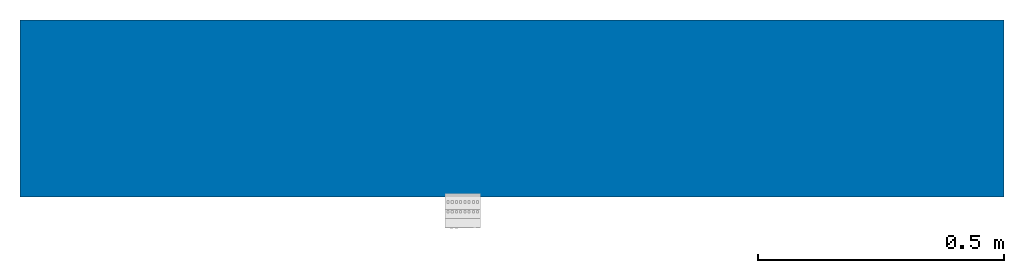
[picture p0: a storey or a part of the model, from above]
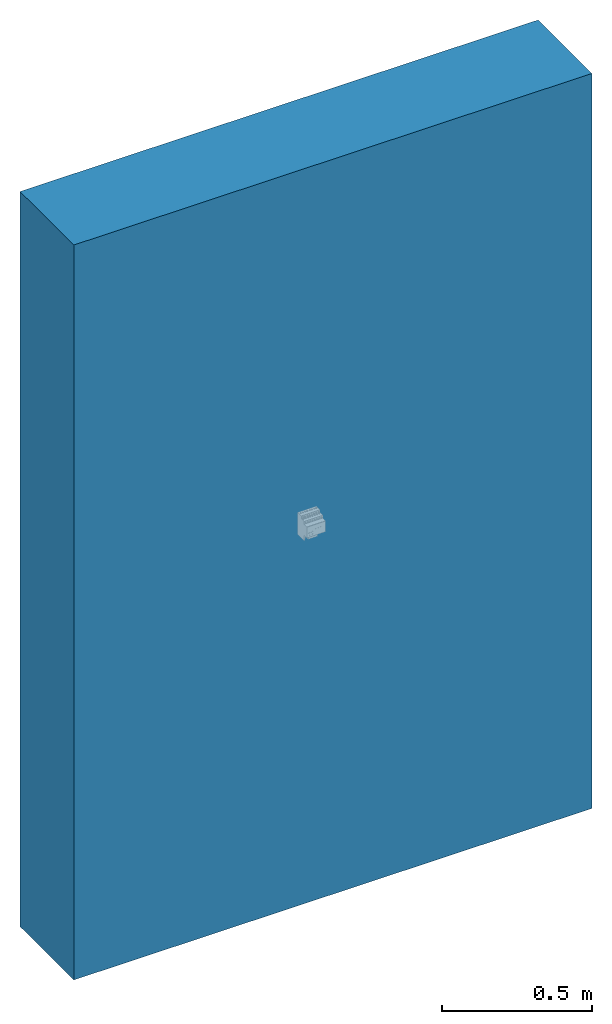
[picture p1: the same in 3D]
Properties of the parts of a building model (IFC2X3)

# File
Description: ViewDefinition [CoordinationView_V2.0]
File name: Projektnummer
Time: 2019-08-29T12:07:32
Written by: The EXPRESS Data Manager Version 5.02.0100.07 : 28 Aug 2013
Made in: 20160225_1515(x64) - Exporter 17.0.416.0 - Alternate UI 17.12.14.0
Comment: STEP Physical File produced by: The EXPRESS Data Manager Version 5.02.0100.07 : 28 Aug 2013 * Module: EDMstepFileFactory/EDMstandAlone * Creation date: Thu Aug 29 12:07:32 2019 * Host: B-BIM-NB-4736 * Database: C:\Users\Enkler\AppData\Local\Temp\{A3307029-4F48-4318-888E-B1E9CAFF832D}\ifc * Database version: 5507 * Database creation date: Thu Aug 29 12:07:31 2019 * Schema: IFC2X3 * Model: DataRepository.ifc * Model creation date: Thu Aug 29 12:07:31 2019 * Header model: DataRepository.ifc_HeaderModel * Header model creation date: Thu Aug 29 12:07:31 2019 * EDMuser: sdai-user * EDMgroup: sdai-group * License ID and type: 5605 : Permanent license. Expiry date: * EDMstepFileFactory options: 020000

# IfcProject, Projektnummer
LongName: Projektname; Phase: Projektstatus

# IfcSite, Default
RefLatitude: 52, 30, 59, 765625; RefLongitude: 13, 23, 59, 998626; RefElevation: 0 m
Sonstige - Kategorie: Projektinformationen; Kundenname: Bauherr; Projektadresse: Projektadresse; Projektausgabedatum: Projekt Datum; Projektname: Projektname; Projektnummer: Projektnummer; Projektstatus: Projektstatus; Verfasser eMail: E-Mail; Verfasser Firma 1: Firma 1; Verfasser Firma 2: Firma 2; Verfasser PLZ Ort: PLZ Ort; Verfasser Strasse: Strasse; Verfasser Telefax: Telefax; Verfasser Telefon: Telefon

# IfcBuilding
Pset_BuildingCommon - NumberOfStoreys: 1
Sonstige - Kategorie: Projektinformationen; Kundenname: Bauherr; Projektadresse: Projektadresse; Projektausgabedatum: Projekt Datum; Projektname: Projektname; Projektnummer: Projektnummer; Projektstatus: Projektstatus; Verfasser eMail: E-Mail; Verfasser Firma 1: Firma 1; Verfasser Firma 2: Firma 2; Verfasser PLZ Ort: PLZ Ort; Verfasser Strasse: Strasse; Verfasser Telefax: Telefax; Verfasser Telefon: Telefon

# IfcBuildingStorey, Ebene 0
LongName: Ebene 0; Elevation: 0 m
Sonstige - Kategorie: Ebenen; Familienname: Ebene; Familie: Ebene: Ebene; Familie und Typ: Ebene: Ebene; Typ: Ebene: Ebene; Typ-ID: Ebene: Ebene
ID-Daten - Typname: Ebene; Tragwerk: no; Gebäudegeschoss: yes; Name: Ebene 0
Grafiken - Farbe: 16711680; Linienmuster: Verdeckt; Linienstärke: 1; Symbol: Beschriftung Ebene: Beschriftung Ebene; Symbol bei Ende 1 Standard: no; Symbol bei Ende 2 Standard: yes
Abhängigkeiten - Basishöhe: Projekt-Basispunkt; Ansicht: 0 m
Abmessungen - Höhe für Berechnung: 0 m

# IfcBuildingElementProxy: GIRA_210800_ENG, GIRA_210800_ENG:GIRA_210800_ENG:389702
In: Ebene 0
Type - Material: White
Type - Abhängigkeiten - Vorgabe-Ansicht: 1.2192 m
Type - Allgemein - Bus connection included: no; Bus connection included YesNo: no; Bus module detachable: no; Bus system KNX: yes; Bus system KNX radio: no; Bus system KNX radio YesNo: no; Bus system KNX YesNo: yes; Bus system LON: no; Bus system LON YesNo: no; Bus system Powernet: no; Bus system Powernet YesNo: no; Bus system radio frequent: no; Bus system radio frequent YesNo: no; Degree of protection (IP) Text: IP20; HeinzeBIM: https://www.heinze.de/bim/dali-gateway-tunable-wh-plus-knx-dra/f92e1bc0089f869e15c3525b0f4f43e7c166bf0a; Local operation/hand operation YesNo: no; Model: Control module; Mounting method: DRA (DIN-rail adapter); Mounting method Text: DRA (DIN-rail adapter); Other bus systems: Other; Other bus systems Text: Other; Radio frequent bidirectional: no; With LED indication YesNo: yes
Type - Daten - Number of outputs: 6; Width in number of modular spacings Number: 4
Type - ID-Daten - Beschreibung: DALI gateway Tun.WH Plus DRA KNX,KNX DALI gateway Tunable White Plus,,,Features:,- Control of lights and other applications with DALI operating units in KNX installations.,- Adjustment of colour temperature for lights with DALI Device Type 8 (Colour Type: Colour Temperature) for Tunable White according to IEC 62386-209.,- Short-circuit protection, overvoltage protection, overload protection.,- Switching and dimming of a maximum of 64 lights with DALI operating devices.,- Up to 6 different Up to addressing types enable control of individual or grouped DALI lights via KNX telegrams.,- Up to 32 independent DALI groups are available for group addressing. These can be expanded by 64 individually addressable DALI device channels.,- Control of DALI operating devices of device type Colour Control" (DALI Device Type 8, Colour Type: Colour Temperature) in specific configuration "Tunable White (TW)". Control of colour temperature vial relative or absolute dimming and also via scenes and effects.,- Central control of all connected DALI components possible (broadcast).,- Manual operation independent of the bus (building site operation with broadcast control). Control of switching condition and brightness.,- Feedback of DALI error status or DALI short circuit and signalling of power supply failure.,- Central switching function.,- Group feedback of all switching conditions possible.,- 16 light scenes.,- Effect control for realising dynamic lighting moods. 16 effects with up to 16 effect steps each. Timer enabling starting and stopping of effects independent of time and day of the week.,Group and device functions:,- Switching and brightness value: Active or passive feedback functions.,- Setting brightness limits (minimum brightness or maximum brightness).,- Dimming behaviour and dimming characteristics can be parameterised.,- Bulb-saving switch-on and switch-off,- Block function or forced setting function can be parameterised.,- Time functions (switch-on switch-off delay, staircase light function - also with advance warning function).,- Elapsed operating time meter.,- DALI power-ON level and DALI system-failure level can be set.,- Reactions in case of bus voltage failure and restoration can be set following ETS programming process.,- Control of colour temperature via absolute dimming and relative dimming, dimming behaviour can be parameterised, adjustable minimum and maximum colour temperature, feedback for current and invalid colour temperature.,Operation of emergency lighting:,- Integration of the device into DALI emergency lighting systems. The DALI gateway is able to integrate DALI standard operating devices for lighting control in accordance with IEC 62386-101 (DALI system) and IEC 62386-102 (control gear) as an emergency light in centrally-powered emergency lighting systems.,- Monitoring for failure of the general power supply.,- Behaviour can be set for the end of emergency mode.,- Brightness and colour temperature adjustable during activate emergency mode.,ETS plug-in:,- DALI initial start-up without additional software comnponents. Identification, addressing and assigning of DALI operating devices takes place in the ETS plug-in.,- Assignment of individual devices to groups is also without programming connection to the device.,- Compatibility check of DALI device type for assigning DALI operating devices.,- Compatibility mode for support of operating devices which are not DALI-compliant.,- Partial DALI start-up.,- Test function of all created DALI groups or DALI operating devices.,- Exporting or importing a template.,- Printing function to create a report.,,Notes :,- Operation of emergency lighting systems:, Statutory and normative specifications vary by country. In any case, the user professional planner should ensure that the specific guidelines are observed.,- VDE approval in accordance with EN 60669-1, EN 60669-2-1.,- Configuration and start-up of the device from ETS 4.2 or ETS 5 (recommendation)."; GTIN: 4010337032878; HAN: 210800; Hersteller: Gira; Typname: DALI gateway Tunable WH Plus KNX DRA; URL: https://www.gira.de/
Type - Sonstige - Kategorie: Elektroinstallationen; Familienname: GIRA_210800_ENG
Pset_BuildingElementProxyCommon - Reference: GIRA_210800_ENG
Pset_ManufacturerTypeInformation - Manufacturer: Gira
Abhängigkeiten - Basisbauteil: Basiswand : MW 24.0 WD 12.0; Ebene: Ebene: Ebene 0; Erhebung: 1.56189 m
Abmessungen - Fläche: 0.0179427 m2; Volumen: 0.000458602 m3
ID-Daten - Kennzeichen: 1
Phasen - Phase erstellt: Phase 1
Sonstige - Bauteillistenebene: Ebene: Ebene 0; Familie: GIRA_210800_ENG: GIRA_210800_ENG; Familie und Typ: GIRA_210800_ENG: GIRA_210800_ENG; Typ: GIRA_210800_ENG: GIRA_210800_ENG; Typ-ID: GIRA_210800_ENG: GIRA_210800_ENG

# IfcWallStandardCase: Basiswand:MW 24.0 WD 12.0, Basiswand:MW 24.0 WD 12.0:388643
In: Ebene 0
Type - PredefinedType: STANDARD; Material: Wärmedämmung - hart 0.12 m, Mauerwerk - Ziegel, verputzt 0.24 m
Type - Analytische Eigenschaften - Absorptionsgrad: 0.7; Rauigkeit: 3; Thermischer Widerstand (R): 3.87302; Thermisch wirksame Masse: 316537; Wärmeübergangskoeffizient (U): 0.258197
Type - Grafiken - Farbfüllung für groben Maßstab: 0; Füllmuster für groben Maßstab: Standard - Füllung
Type - ID-Daten - Beschreibung: Mauerwerk 24.0 cm, Wärmedämmung 12.0 cm; Typenkommentare: Mehrschaliges Mauerwerk; Typname: MW 24.0 WD 12.0
Type - Konstruktion - Abschluss an Öffnungen: Keine; Abschluss an Wänden: Keine; Breite: 0.36 m; Funktion: Außen
Type - Materialien und Oberflächen - Tragendes Material: Mauerwerk - Ziegel, verputzt
Type - Sonstige - Kategorie: Wände; Familienname: Basiswand
Abhängigkeiten - Abhängigkeit oben: Ebene: Ebene 1; Abhängigkeit unten: Ebene: Ebene 0; Basislinie: Wandachse; Für Körper: no; Nicht verknüpfte Höhe: 3 m; Oberkante ist fixiert.: no; Raumbegrenzung: yes; Unterkante ist fixiert: no; Verlängerungsabstand oben: 0 m; Verlängerungsabstand unten: 0 m; Versatz oben: 0 m; Versatz unten: 0 m
Abmessungen - Fläche: 6 m2; Länge: 2 m; Volumen: 2.16 m3
Phasen - Phase erstellt: Phase 1
Sonstige - Familie: Basiswand: MW 24.0 WD 12.0; Familie und Typ: Basiswand: MW 24.0 WD 12.0; Typ: Basiswand: MW 24.0 WD 12.0; Typ-ID: Basiswand: MW 24.0 WD 12.0
Tragwerk - Berechnungsmodell aktivieren: no; Tragwerk: no; Tragwerksverwendung: Nichttragend
Pset_WallCommon - Reference: MW 24.0 WD 12.0; LoadBearing: no; ExtendToStructure: no; IsExternal: yes; ThermalTransmittance: 0.258197 kg/K/s3
